One B-rep face of a CAD part: STEP entity #33061.
In plain terms, the planar face has unit normal (0, -1, 0).
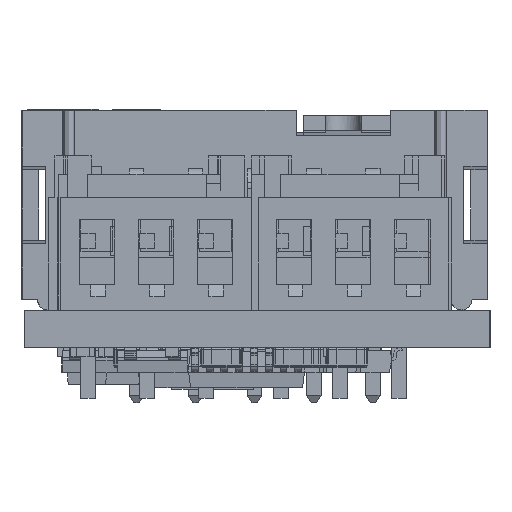
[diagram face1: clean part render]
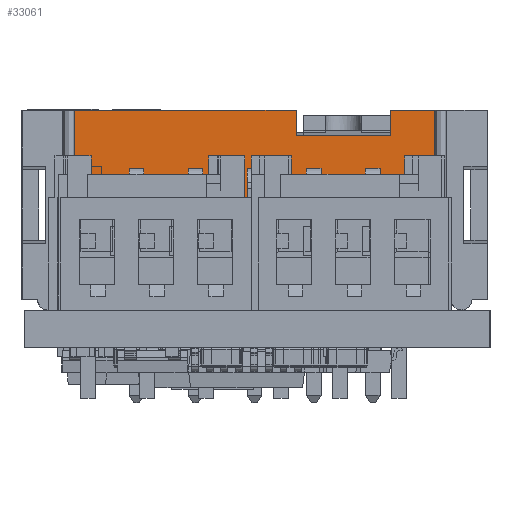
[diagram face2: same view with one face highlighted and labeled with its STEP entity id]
Its self-contained STEP definition (entity closure, numbers rounded to 3 decimals):
#33012 = EDGE_CURVE('',#33013,#33015,#33017,.T.);
#33013 = VERTEX_POINT('',#33014);
#33014 = CARTESIAN_POINT('',(7.75,2.466,8.585));
#33015 = VERTEX_POINT('',#33016);
#33016 = CARTESIAN_POINT('',(7.75,2.466,0.457));
#33017 = B_SPLINE_CURVE_WITH_KNOTS('',3,(#33018,#33019,#33020,#33021),
  .UNSPECIFIED.,.F.,.F.,(4,4),(0.,1.),.PIECEWISE_BEZIER_KNOTS.);
#33018 = CARTESIAN_POINT('',(7.75,2.466,8.585));
#33019 = CARTESIAN_POINT('',(7.75,2.466,5.876));
#33020 = CARTESIAN_POINT('',(7.75,2.466,3.167));
#33021 = CARTESIAN_POINT('',(7.75,2.466,0.457));
#33061 = ADVANCED_FACE('',(#33062),#33162,.T.);
#33062 = FACE_BOUND('',#33063,.T.);
#33063 = EDGE_LOOP('',(#33064,#33075,#33084,#33093,#33102,#33109,#33110,
    #33119,#33128,#33137,#33146,#33155));
#33064 = ORIENTED_EDGE('',*,*,#33065,.T.);
#33065 = EDGE_CURVE('',#33066,#33068,#33070,.T.);
#33066 = VERTEX_POINT('',#33067);
#33067 = CARTESIAN_POINT('',(-6.059,2.466,8.585));
#33068 = VERTEX_POINT('',#33069);
#33069 = CARTESIAN_POINT('',(-7.744,2.466,8.585));
#33070 = B_SPLINE_CURVE_WITH_KNOTS('',3,(#33071,#33072,#33073,#33074),
  .UNSPECIFIED.,.F.,.F.,(4,4),(0.823,1.),
  .PIECEWISE_BEZIER_KNOTS.);
#33071 = CARTESIAN_POINT('',(-6.059,2.466,8.585));
#33072 = CARTESIAN_POINT('',(-6.621,2.466,8.585));
#33073 = CARTESIAN_POINT('',(-7.182,2.466,8.585));
#33074 = CARTESIAN_POINT('',(-7.744,2.466,8.585));
#33075 = ORIENTED_EDGE('',*,*,#33076,.F.);
#33076 = EDGE_CURVE('',#33077,#33068,#33079,.T.);
#33077 = VERTEX_POINT('',#33078);
#33078 = CARTESIAN_POINT('',(-7.744,2.466,0.457));
#33079 = B_SPLINE_CURVE_WITH_KNOTS('',3,(#33080,#33081,#33082,#33083),
  .UNSPECIFIED.,.F.,.F.,(4,4),(0.,1.),.PIECEWISE_BEZIER_KNOTS.);
#33080 = CARTESIAN_POINT('',(-7.744,2.466,0.457));
#33081 = CARTESIAN_POINT('',(-7.744,2.466,3.167));
#33082 = CARTESIAN_POINT('',(-7.744,2.466,5.876));
#33083 = CARTESIAN_POINT('',(-7.744,2.466,8.585));
#33084 = ORIENTED_EDGE('',*,*,#33085,.F.);
#33085 = EDGE_CURVE('',#33086,#33077,#33088,.T.);
#33086 = VERTEX_POINT('',#33087);
#33087 = CARTESIAN_POINT('',(-6.059,2.466,0.457));
#33088 = B_SPLINE_CURVE_WITH_KNOTS('',3,(#33089,#33090,#33091,#33092),
  .UNSPECIFIED.,.F.,.F.,(4,4),(0.891,1.),
  .PIECEWISE_BEZIER_KNOTS.);
#33089 = CARTESIAN_POINT('',(-6.059,2.466,0.457));
#33090 = CARTESIAN_POINT('',(-6.621,2.466,0.457));
#33091 = CARTESIAN_POINT('',(-7.182,2.466,0.457));
#33092 = CARTESIAN_POINT('',(-7.744,2.466,0.457));
#33093 = ORIENTED_EDGE('',*,*,#33094,.F.);
#33094 = EDGE_CURVE('',#33095,#33086,#33097,.T.);
#33095 = VERTEX_POINT('',#33096);
#33096 = CARTESIAN_POINT('',(6.066,2.466,0.457));
#33097 = B_SPLINE_CURVE_WITH_KNOTS('',3,(#33098,#33099,#33100,#33101),
  .UNSPECIFIED.,.F.,.F.,(4,4),(0.109,0.891),
  .PIECEWISE_BEZIER_KNOTS.);
#33098 = CARTESIAN_POINT('',(6.066,2.466,0.457));
#33099 = CARTESIAN_POINT('',(2.024,2.466,0.457));
#33100 = CARTESIAN_POINT('',(-2.018,2.466,0.457));
#33101 = CARTESIAN_POINT('',(-6.059,2.466,0.457));
#33102 = ORIENTED_EDGE('',*,*,#33103,.F.);
#33103 = EDGE_CURVE('',#33015,#33095,#33104,.T.);
#33104 = B_SPLINE_CURVE_WITH_KNOTS('',3,(#33105,#33106,#33107,#33108),
  .UNSPECIFIED.,.F.,.F.,(4,4),(0.,0.109),
  .PIECEWISE_BEZIER_KNOTS.);
#33105 = CARTESIAN_POINT('',(7.75,2.466,0.457));
#33106 = CARTESIAN_POINT('',(7.189,2.466,0.457));
#33107 = CARTESIAN_POINT('',(6.627,2.466,0.457));
#33108 = CARTESIAN_POINT('',(6.066,2.466,0.457));
#33109 = ORIENTED_EDGE('',*,*,#33012,.F.);
#33110 = ORIENTED_EDGE('',*,*,#33111,.F.);
#33111 = EDGE_CURVE('',#33112,#33013,#33114,.T.);
#33112 = VERTEX_POINT('',#33113);
#33113 = CARTESIAN_POINT('',(6.066,2.466,8.585));
#33114 = B_SPLINE_CURVE_WITH_KNOTS('',3,(#33115,#33116,#33117,#33118),
  .UNSPECIFIED.,.F.,.F.,(4,4),(0.116,1.),
  .PIECEWISE_BEZIER_KNOTS.);
#33115 = CARTESIAN_POINT('',(6.066,2.466,8.585));
#33116 = CARTESIAN_POINT('',(6.627,2.466,8.585));
#33117 = CARTESIAN_POINT('',(7.189,2.466,8.585));
#33118 = CARTESIAN_POINT('',(7.75,2.466,8.585));
#33119 = ORIENTED_EDGE('',*,*,#33120,.F.);
#33120 = EDGE_CURVE('',#33121,#33112,#33123,.T.);
#33121 = VERTEX_POINT('',#33122);
#33122 = CARTESIAN_POINT('',(5.845,2.466,8.585));
#33123 = B_SPLINE_CURVE_WITH_KNOTS('',3,(#33124,#33125,#33126,#33127),
  .UNSPECIFIED.,.F.,.F.,(4,4),(0.,0.116),
  .PIECEWISE_BEZIER_KNOTS.);
#33124 = CARTESIAN_POINT('',(5.845,2.466,8.585));
#33125 = CARTESIAN_POINT('',(5.919,2.466,8.585));
#33126 = CARTESIAN_POINT('',(5.992,2.466,8.585));
#33127 = CARTESIAN_POINT('',(6.066,2.466,8.585));
#33128 = ORIENTED_EDGE('',*,*,#33129,.F.);
#33129 = EDGE_CURVE('',#33130,#33121,#33132,.T.);
#33130 = VERTEX_POINT('',#33131);
#33131 = CARTESIAN_POINT('',(5.845,2.466,7.487));
#33132 = B_SPLINE_CURVE_WITH_KNOTS('',3,(#33133,#33134,#33135,#33136),
  .UNSPECIFIED.,.F.,.F.,(4,4),(0.,1.),.PIECEWISE_BEZIER_KNOTS.);
#33133 = CARTESIAN_POINT('',(5.845,2.466,7.487));
#33134 = CARTESIAN_POINT('',(5.845,2.466,7.853));
#33135 = CARTESIAN_POINT('',(5.845,2.466,8.219));
#33136 = CARTESIAN_POINT('',(5.845,2.466,8.585));
#33137 = ORIENTED_EDGE('',*,*,#33138,.F.);
#33138 = EDGE_CURVE('',#33139,#33130,#33141,.T.);
#33139 = VERTEX_POINT('',#33140);
#33140 = CARTESIAN_POINT('',(1.781,2.466,7.487));
#33141 = B_SPLINE_CURVE_WITH_KNOTS('',3,(#33142,#33143,#33144,#33145),
  .UNSPECIFIED.,.F.,.F.,(4,4),(0.,1.),.PIECEWISE_BEZIER_KNOTS.);
#33142 = CARTESIAN_POINT('',(1.781,2.466,7.487));
#33143 = CARTESIAN_POINT('',(3.136,2.466,
    7.487));
#33144 = CARTESIAN_POINT('',(4.491,2.466,
    7.487));
#33145 = CARTESIAN_POINT('',(5.845,2.466,7.487));
#33146 = ORIENTED_EDGE('',*,*,#33147,.F.);
#33147 = EDGE_CURVE('',#33148,#33139,#33150,.T.);
#33148 = VERTEX_POINT('',#33149);
#33149 = CARTESIAN_POINT('',(1.781,2.466,8.585));
#33150 = B_SPLINE_CURVE_WITH_KNOTS('',3,(#33151,#33152,#33153,#33154),
  .UNSPECIFIED.,.F.,.F.,(4,4),(0.,1.),.PIECEWISE_BEZIER_KNOTS.);
#33151 = CARTESIAN_POINT('',(1.781,2.466,8.585));
#33152 = CARTESIAN_POINT('',(1.781,2.466,8.219));
#33153 = CARTESIAN_POINT('',(1.781,2.466,7.853));
#33154 = CARTESIAN_POINT('',(1.781,2.466,7.487));
#33155 = ORIENTED_EDGE('',*,*,#33156,.T.);
#33156 = EDGE_CURVE('',#33148,#33066,#33157,.T.);
#33157 = B_SPLINE_CURVE_WITH_KNOTS('',3,(#33158,#33159,#33160,#33161),
  .UNSPECIFIED.,.F.,.F.,(4,4),(0.,0.823),
  .PIECEWISE_BEZIER_KNOTS.);
#33158 = CARTESIAN_POINT('',(1.781,2.466,8.585));
#33159 = CARTESIAN_POINT('',(-0.832,2.466,8.585));
#33160 = CARTESIAN_POINT('',(-3.446,2.466,8.585));
#33161 = CARTESIAN_POINT('',(-6.059,2.466,8.585));
#33162 = PLANE('',#33163);
#33163 = AXIS2_PLACEMENT_3D('',#33164,#33165,#33166);
#33164 = CARTESIAN_POINT('',(-8.519,2.466,8.992));
#33165 = DIRECTION('',(0.,-1.,0.));
#33166 = DIRECTION('',(0.,0.,-1.));
